# Generated by FakeRAM 2.0
VERSION 5.7 ;
BUSBITCHARS "[]" ;
PROPERTYDEFINITIONS
  MACRO width INTEGER ;
  MACRO depth INTEGER ;
  MACRO banks INTEGER ;
END PROPERTYDEFINITIONS
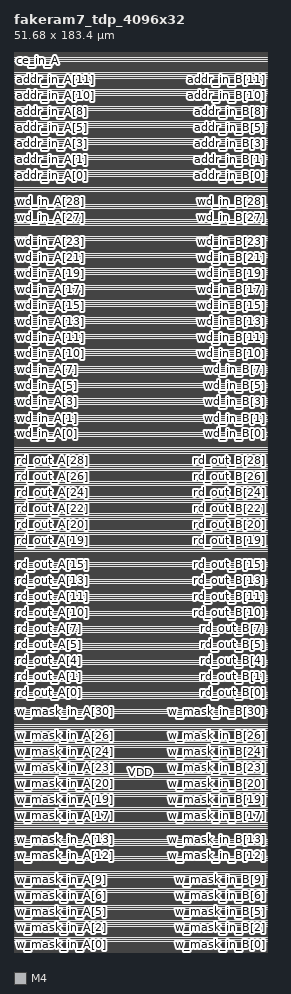
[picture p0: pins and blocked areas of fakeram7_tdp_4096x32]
MACRO fakeram7_tdp_4096x32
  PROPERTY width 32 ;
  PROPERTY depth 4096 ;
  PROPERTY banks 8 ;
  FOREIGN fakeram7_tdp_4096x32 0 0 ;
  SYMMETRY X Y ;
  SIZE 51.680 BY 183.400 ;
  CLASS BLOCK ;
  PIN w_mask_in_A[0]
    DIRECTION INPUT ;
    USE SIGNAL ;
    SHAPE ABUTMENT ;
    PORT
      LAYER M4 ;
      RECT 0.000 0.048 0.024 0.072 ;
    END
  END w_mask_in_A[0]
  PIN w_mask_in_B[0]
    DIRECTION INPUT ;
    USE SIGNAL ;
    SHAPE ABUTMENT ;
    PORT
      LAYER M4 ;
      RECT 51.656 0.048 51.680 0.072 ;
    END
  END w_mask_in_B[0]
  PIN w_mask_in_A[1]
    DIRECTION INPUT ;
    USE SIGNAL ;
    SHAPE ABUTMENT ;
    PORT
      LAYER M4 ;
      RECT 0.000 1.680 0.024 1.704 ;
    END
  END w_mask_in_A[1]
  PIN w_mask_in_B[1]
    DIRECTION INPUT ;
    USE SIGNAL ;
    SHAPE ABUTMENT ;
    PORT
      LAYER M4 ;
      RECT 51.656 1.680 51.680 1.704 ;
    END
  END w_mask_in_B[1]
  PIN w_mask_in_A[2]
    DIRECTION INPUT ;
    USE SIGNAL ;
    SHAPE ABUTMENT ;
    PORT
      LAYER M4 ;
      RECT 0.000 3.312 0.024 3.336 ;
    END
  END w_mask_in_A[2]
  PIN w_mask_in_B[2]
    DIRECTION INPUT ;
    USE SIGNAL ;
    SHAPE ABUTMENT ;
    PORT
      LAYER M4 ;
      RECT 51.656 3.312 51.680 3.336 ;
    END
  END w_mask_in_B[2]
  PIN w_mask_in_A[3]
    DIRECTION INPUT ;
    USE SIGNAL ;
    SHAPE ABUTMENT ;
    PORT
      LAYER M4 ;
      RECT 0.000 4.944 0.024 4.968 ;
    END
  END w_mask_in_A[3]
  PIN w_mask_in_B[3]
    DIRECTION INPUT ;
    USE SIGNAL ;
    SHAPE ABUTMENT ;
    PORT
      LAYER M4 ;
      RECT 51.656 4.944 51.680 4.968 ;
    END
  END w_mask_in_B[3]
  PIN w_mask_in_A[4]
    DIRECTION INPUT ;
    USE SIGNAL ;
    SHAPE ABUTMENT ;
    PORT
      LAYER M4 ;
      RECT 0.000 6.576 0.024 6.600 ;
    END
  END w_mask_in_A[4]
  PIN w_mask_in_B[4]
    DIRECTION INPUT ;
    USE SIGNAL ;
    SHAPE ABUTMENT ;
    PORT
      LAYER M4 ;
      RECT 51.656 6.576 51.680 6.600 ;
    END
  END w_mask_in_B[4]
  PIN w_mask_in_A[5]
    DIRECTION INPUT ;
    USE SIGNAL ;
    SHAPE ABUTMENT ;
    PORT
      LAYER M4 ;
      RECT 0.000 8.208 0.024 8.232 ;
    END
  END w_mask_in_A[5]
  PIN w_mask_in_B[5]
    DIRECTION INPUT ;
    USE SIGNAL ;
    SHAPE ABUTMENT ;
    PORT
      LAYER M4 ;
      RECT 51.656 8.208 51.680 8.232 ;
    END
  END w_mask_in_B[5]
  PIN w_mask_in_A[6]
    DIRECTION INPUT ;
    USE SIGNAL ;
    SHAPE ABUTMENT ;
    PORT
      LAYER M4 ;
      RECT 0.000 9.840 0.024 9.864 ;
    END
  END w_mask_in_A[6]
  PIN w_mask_in_B[6]
    DIRECTION INPUT ;
    USE SIGNAL ;
    SHAPE ABUTMENT ;
    PORT
      LAYER M4 ;
      RECT 51.656 9.840 51.680 9.864 ;
    END
  END w_mask_in_B[6]
  PIN w_mask_in_A[7]
    DIRECTION INPUT ;
    USE SIGNAL ;
    SHAPE ABUTMENT ;
    PORT
      LAYER M4 ;
      RECT 0.000 11.472 0.024 11.496 ;
    END
  END w_mask_in_A[7]
  PIN w_mask_in_B[7]
    DIRECTION INPUT ;
    USE SIGNAL ;
    SHAPE ABUTMENT ;
    PORT
      LAYER M4 ;
      RECT 51.656 11.472 51.680 11.496 ;
    END
  END w_mask_in_B[7]
  PIN w_mask_in_A[8]
    DIRECTION INPUT ;
    USE SIGNAL ;
    SHAPE ABUTMENT ;
    PORT
      LAYER M4 ;
      RECT 0.000 13.104 0.024 13.128 ;
    END
  END w_mask_in_A[8]
  PIN w_mask_in_B[8]
    DIRECTION INPUT ;
    USE SIGNAL ;
    SHAPE ABUTMENT ;
    PORT
      LAYER M4 ;
      RECT 51.656 13.104 51.680 13.128 ;
    END
  END w_mask_in_B[8]
  PIN w_mask_in_A[9]
    DIRECTION INPUT ;
    USE SIGNAL ;
    SHAPE ABUTMENT ;
    PORT
      LAYER M4 ;
      RECT 0.000 14.736 0.024 14.760 ;
    END
  END w_mask_in_A[9]
  PIN w_mask_in_B[9]
    DIRECTION INPUT ;
    USE SIGNAL ;
    SHAPE ABUTMENT ;
    PORT
      LAYER M4 ;
      RECT 51.656 14.736 51.680 14.760 ;
    END
  END w_mask_in_B[9]
  PIN w_mask_in_A[10]
    DIRECTION INPUT ;
    USE SIGNAL ;
    SHAPE ABUTMENT ;
    PORT
      LAYER M4 ;
      RECT 0.000 16.368 0.024 16.392 ;
    END
  END w_mask_in_A[10]
  PIN w_mask_in_B[10]
    DIRECTION INPUT ;
    USE SIGNAL ;
    SHAPE ABUTMENT ;
    PORT
      LAYER M4 ;
      RECT 51.656 16.368 51.680 16.392 ;
    END
  END w_mask_in_B[10]
  PIN w_mask_in_A[11]
    DIRECTION INPUT ;
    USE SIGNAL ;
    SHAPE ABUTMENT ;
    PORT
      LAYER M4 ;
      RECT 0.000 18.000 0.024 18.024 ;
    END
  END w_mask_in_A[11]
  PIN w_mask_in_B[11]
    DIRECTION INPUT ;
    USE SIGNAL ;
    SHAPE ABUTMENT ;
    PORT
      LAYER M4 ;
      RECT 51.656 18.000 51.680 18.024 ;
    END
  END w_mask_in_B[11]
  PIN w_mask_in_A[12]
    DIRECTION INPUT ;
    USE SIGNAL ;
    SHAPE ABUTMENT ;
    PORT
      LAYER M4 ;
      RECT 0.000 19.632 0.024 19.656 ;
    END
  END w_mask_in_A[12]
  PIN w_mask_in_B[12]
    DIRECTION INPUT ;
    USE SIGNAL ;
    SHAPE ABUTMENT ;
    PORT
      LAYER M4 ;
      RECT 51.656 19.632 51.680 19.656 ;
    END
  END w_mask_in_B[12]
  PIN w_mask_in_A[13]
    DIRECTION INPUT ;
    USE SIGNAL ;
    SHAPE ABUTMENT ;
    PORT
      LAYER M4 ;
      RECT 0.000 21.264 0.024 21.288 ;
    END
  END w_mask_in_A[13]
  PIN w_mask_in_B[13]
    DIRECTION INPUT ;
    USE SIGNAL ;
    SHAPE ABUTMENT ;
    PORT
      LAYER M4 ;
      RECT 51.656 21.264 51.680 21.288 ;
    END
  END w_mask_in_B[13]
  PIN w_mask_in_A[14]
    DIRECTION INPUT ;
    USE SIGNAL ;
    SHAPE ABUTMENT ;
    PORT
      LAYER M4 ;
      RECT 0.000 22.896 0.024 22.920 ;
    END
  END w_mask_in_A[14]
  PIN w_mask_in_B[14]
    DIRECTION INPUT ;
    USE SIGNAL ;
    SHAPE ABUTMENT ;
    PORT
      LAYER M4 ;
      RECT 51.656 22.896 51.680 22.920 ;
    END
  END w_mask_in_B[14]
  PIN w_mask_in_A[15]
    DIRECTION INPUT ;
    USE SIGNAL ;
    SHAPE ABUTMENT ;
    PORT
      LAYER M4 ;
      RECT 0.000 24.528 0.024 24.552 ;
    END
  END w_mask_in_A[15]
  PIN w_mask_in_B[15]
    DIRECTION INPUT ;
    USE SIGNAL ;
    SHAPE ABUTMENT ;
    PORT
      LAYER M4 ;
      RECT 51.656 24.528 51.680 24.552 ;
    END
  END w_mask_in_B[15]
  PIN w_mask_in_A[16]
    DIRECTION INPUT ;
    USE SIGNAL ;
    SHAPE ABUTMENT ;
    PORT
      LAYER M4 ;
      RECT 0.000 26.160 0.024 26.184 ;
    END
  END w_mask_in_A[16]
  PIN w_mask_in_B[16]
    DIRECTION INPUT ;
    USE SIGNAL ;
    SHAPE ABUTMENT ;
    PORT
      LAYER M4 ;
      RECT 51.656 26.160 51.680 26.184 ;
    END
  END w_mask_in_B[16]
  PIN w_mask_in_A[17]
    DIRECTION INPUT ;
    USE SIGNAL ;
    SHAPE ABUTMENT ;
    PORT
      LAYER M4 ;
      RECT 0.000 27.792 0.024 27.816 ;
    END
  END w_mask_in_A[17]
  PIN w_mask_in_B[17]
    DIRECTION INPUT ;
    USE SIGNAL ;
    SHAPE ABUTMENT ;
    PORT
      LAYER M4 ;
      RECT 51.656 27.792 51.680 27.816 ;
    END
  END w_mask_in_B[17]
  PIN w_mask_in_A[18]
    DIRECTION INPUT ;
    USE SIGNAL ;
    SHAPE ABUTMENT ;
    PORT
      LAYER M4 ;
      RECT 0.000 29.424 0.024 29.448 ;
    END
  END w_mask_in_A[18]
  PIN w_mask_in_B[18]
    DIRECTION INPUT ;
    USE SIGNAL ;
    SHAPE ABUTMENT ;
    PORT
      LAYER M4 ;
      RECT 51.656 29.424 51.680 29.448 ;
    END
  END w_mask_in_B[18]
  PIN w_mask_in_A[19]
    DIRECTION INPUT ;
    USE SIGNAL ;
    SHAPE ABUTMENT ;
    PORT
      LAYER M4 ;
      RECT 0.000 31.056 0.024 31.080 ;
    END
  END w_mask_in_A[19]
  PIN w_mask_in_B[19]
    DIRECTION INPUT ;
    USE SIGNAL ;
    SHAPE ABUTMENT ;
    PORT
      LAYER M4 ;
      RECT 51.656 31.056 51.680 31.080 ;
    END
  END w_mask_in_B[19]
  PIN w_mask_in_A[20]
    DIRECTION INPUT ;
    USE SIGNAL ;
    SHAPE ABUTMENT ;
    PORT
      LAYER M4 ;
      RECT 0.000 32.688 0.024 32.712 ;
    END
  END w_mask_in_A[20]
  PIN w_mask_in_B[20]
    DIRECTION INPUT ;
    USE SIGNAL ;
    SHAPE ABUTMENT ;
    PORT
      LAYER M4 ;
      RECT 51.656 32.688 51.680 32.712 ;
    END
  END w_mask_in_B[20]
  PIN w_mask_in_A[21]
    DIRECTION INPUT ;
    USE SIGNAL ;
    SHAPE ABUTMENT ;
    PORT
      LAYER M4 ;
      RECT 0.000 34.320 0.024 34.344 ;
    END
  END w_mask_in_A[21]
  PIN w_mask_in_B[21]
    DIRECTION INPUT ;
    USE SIGNAL ;
    SHAPE ABUTMENT ;
    PORT
      LAYER M4 ;
      RECT 51.656 34.320 51.680 34.344 ;
    END
  END w_mask_in_B[21]
  PIN w_mask_in_A[22]
    DIRECTION INPUT ;
    USE SIGNAL ;
    SHAPE ABUTMENT ;
    PORT
      LAYER M4 ;
      RECT 0.000 35.952 0.024 35.976 ;
    END
  END w_mask_in_A[22]
  PIN w_mask_in_B[22]
    DIRECTION INPUT ;
    USE SIGNAL ;
    SHAPE ABUTMENT ;
    PORT
      LAYER M4 ;
      RECT 51.656 35.952 51.680 35.976 ;
    END
  END w_mask_in_B[22]
  PIN w_mask_in_A[23]
    DIRECTION INPUT ;
    USE SIGNAL ;
    SHAPE ABUTMENT ;
    PORT
      LAYER M4 ;
      RECT 0.000 37.584 0.024 37.608 ;
    END
  END w_mask_in_A[23]
  PIN w_mask_in_B[23]
    DIRECTION INPUT ;
    USE SIGNAL ;
    SHAPE ABUTMENT ;
    PORT
      LAYER M4 ;
      RECT 51.656 37.584 51.680 37.608 ;
    END
  END w_mask_in_B[23]
  PIN w_mask_in_A[24]
    DIRECTION INPUT ;
    USE SIGNAL ;
    SHAPE ABUTMENT ;
    PORT
      LAYER M4 ;
      RECT 0.000 39.216 0.024 39.240 ;
    END
  END w_mask_in_A[24]
  PIN w_mask_in_B[24]
    DIRECTION INPUT ;
    USE SIGNAL ;
    SHAPE ABUTMENT ;
    PORT
      LAYER M4 ;
      RECT 51.656 39.216 51.680 39.240 ;
    END
  END w_mask_in_B[24]
  PIN w_mask_in_A[25]
    DIRECTION INPUT ;
    USE SIGNAL ;
    SHAPE ABUTMENT ;
    PORT
      LAYER M4 ;
      RECT 0.000 40.848 0.024 40.872 ;
    END
  END w_mask_in_A[25]
  PIN w_mask_in_B[25]
    DIRECTION INPUT ;
    USE SIGNAL ;
    SHAPE ABUTMENT ;
    PORT
      LAYER M4 ;
      RECT 51.656 40.848 51.680 40.872 ;
    END
  END w_mask_in_B[25]
  PIN w_mask_in_A[26]
    DIRECTION INPUT ;
    USE SIGNAL ;
    SHAPE ABUTMENT ;
    PORT
      LAYER M4 ;
      RECT 0.000 42.480 0.024 42.504 ;
    END
  END w_mask_in_A[26]
  PIN w_mask_in_B[26]
    DIRECTION INPUT ;
    USE SIGNAL ;
    SHAPE ABUTMENT ;
    PORT
      LAYER M4 ;
      RECT 51.656 42.480 51.680 42.504 ;
    END
  END w_mask_in_B[26]
  PIN w_mask_in_A[27]
    DIRECTION INPUT ;
    USE SIGNAL ;
    SHAPE ABUTMENT ;
    PORT
      LAYER M4 ;
      RECT 0.000 44.112 0.024 44.136 ;
    END
  END w_mask_in_A[27]
  PIN w_mask_in_B[27]
    DIRECTION INPUT ;
    USE SIGNAL ;
    SHAPE ABUTMENT ;
    PORT
      LAYER M4 ;
      RECT 51.656 44.112 51.680 44.136 ;
    END
  END w_mask_in_B[27]
  PIN w_mask_in_A[28]
    DIRECTION INPUT ;
    USE SIGNAL ;
    SHAPE ABUTMENT ;
    PORT
      LAYER M4 ;
      RECT 0.000 45.744 0.024 45.768 ;
    END
  END w_mask_in_A[28]
  PIN w_mask_in_B[28]
    DIRECTION INPUT ;
    USE SIGNAL ;
    SHAPE ABUTMENT ;
    PORT
      LAYER M4 ;
      RECT 51.656 45.744 51.680 45.768 ;
    END
  END w_mask_in_B[28]
  PIN w_mask_in_A[29]
    DIRECTION INPUT ;
    USE SIGNAL ;
    SHAPE ABUTMENT ;
    PORT
      LAYER M4 ;
      RECT 0.000 47.376 0.024 47.400 ;
    END
  END w_mask_in_A[29]
  PIN w_mask_in_B[29]
    DIRECTION INPUT ;
    USE SIGNAL ;
    SHAPE ABUTMENT ;
    PORT
      LAYER M4 ;
      RECT 51.656 47.376 51.680 47.400 ;
    END
  END w_mask_in_B[29]
  PIN w_mask_in_A[30]
    DIRECTION INPUT ;
    USE SIGNAL ;
    SHAPE ABUTMENT ;
    PORT
      LAYER M4 ;
      RECT 0.000 49.008 0.024 49.032 ;
    END
  END w_mask_in_A[30]
  PIN w_mask_in_B[30]
    DIRECTION INPUT ;
    USE SIGNAL ;
    SHAPE ABUTMENT ;
    PORT
      LAYER M4 ;
      RECT 51.656 49.008 51.680 49.032 ;
    END
  END w_mask_in_B[30]
  PIN w_mask_in_A[31]
    DIRECTION INPUT ;
    USE SIGNAL ;
    SHAPE ABUTMENT ;
    PORT
      LAYER M4 ;
      RECT 0.000 50.640 0.024 50.664 ;
    END
  END w_mask_in_A[31]
  PIN w_mask_in_B[31]
    DIRECTION INPUT ;
    USE SIGNAL ;
    SHAPE ABUTMENT ;
    PORT
      LAYER M4 ;
      RECT 51.656 50.640 51.680 50.664 ;
    END
  END w_mask_in_B[31]
  PIN rd_out_A[0]
    DIRECTION OUTPUT ;
    USE SIGNAL ;
    SHAPE ABUTMENT ;
    PORT
      LAYER M4 ;
      RECT 0.000 52.800 0.024 52.824 ;
    END
  END rd_out_A[0]
  PIN rd_out_B[0]
    DIRECTION OUTPUT ;
    USE SIGNAL ;
    SHAPE ABUTMENT ;
    PORT
      LAYER M4 ;
      RECT 51.656 52.800 51.680 52.824 ;
    END
  END rd_out_B[0]
  PIN rd_out_A[1]
    DIRECTION OUTPUT ;
    USE SIGNAL ;
    SHAPE ABUTMENT ;
    PORT
      LAYER M4 ;
      RECT 0.000 54.432 0.024 54.456 ;
    END
  END rd_out_A[1]
  PIN rd_out_B[1]
    DIRECTION OUTPUT ;
    USE SIGNAL ;
    SHAPE ABUTMENT ;
    PORT
      LAYER M4 ;
      RECT 51.656 54.432 51.680 54.456 ;
    END
  END rd_out_B[1]
  PIN rd_out_A[2]
    DIRECTION OUTPUT ;
    USE SIGNAL ;
    SHAPE ABUTMENT ;
    PORT
      LAYER M4 ;
      RECT 0.000 56.064 0.024 56.088 ;
    END
  END rd_out_A[2]
  PIN rd_out_B[2]
    DIRECTION OUTPUT ;
    USE SIGNAL ;
    SHAPE ABUTMENT ;
    PORT
      LAYER M4 ;
      RECT 51.656 56.064 51.680 56.088 ;
    END
  END rd_out_B[2]
  PIN rd_out_A[3]
    DIRECTION OUTPUT ;
    USE SIGNAL ;
    SHAPE ABUTMENT ;
    PORT
      LAYER M4 ;
      RECT 0.000 57.696 0.024 57.720 ;
    END
  END rd_out_A[3]
  PIN rd_out_B[3]
    DIRECTION OUTPUT ;
    USE SIGNAL ;
    SHAPE ABUTMENT ;
    PORT
      LAYER M4 ;
      RECT 51.656 57.696 51.680 57.720 ;
    END
  END rd_out_B[3]
  PIN rd_out_A[4]
    DIRECTION OUTPUT ;
    USE SIGNAL ;
    SHAPE ABUTMENT ;
    PORT
      LAYER M4 ;
      RECT 0.000 59.328 0.024 59.352 ;
    END
  END rd_out_A[4]
  PIN rd_out_B[4]
    DIRECTION OUTPUT ;
    USE SIGNAL ;
    SHAPE ABUTMENT ;
    PORT
      LAYER M4 ;
      RECT 51.656 59.328 51.680 59.352 ;
    END
  END rd_out_B[4]
  PIN rd_out_A[5]
    DIRECTION OUTPUT ;
    USE SIGNAL ;
    SHAPE ABUTMENT ;
    PORT
      LAYER M4 ;
      RECT 0.000 60.960 0.024 60.984 ;
    END
  END rd_out_A[5]
  PIN rd_out_B[5]
    DIRECTION OUTPUT ;
    USE SIGNAL ;
    SHAPE ABUTMENT ;
    PORT
      LAYER M4 ;
      RECT 51.656 60.960 51.680 60.984 ;
    END
  END rd_out_B[5]
  PIN rd_out_A[6]
    DIRECTION OUTPUT ;
    USE SIGNAL ;
    SHAPE ABUTMENT ;
    PORT
      LAYER M4 ;
      RECT 0.000 62.592 0.024 62.616 ;
    END
  END rd_out_A[6]
  PIN rd_out_B[6]
    DIRECTION OUTPUT ;
    USE SIGNAL ;
    SHAPE ABUTMENT ;
    PORT
      LAYER M4 ;
      RECT 51.656 62.592 51.680 62.616 ;
    END
  END rd_out_B[6]
  PIN rd_out_A[7]
    DIRECTION OUTPUT ;
    USE SIGNAL ;
    SHAPE ABUTMENT ;
    PORT
      LAYER M4 ;
      RECT 0.000 64.224 0.024 64.248 ;
    END
  END rd_out_A[7]
  PIN rd_out_B[7]
    DIRECTION OUTPUT ;
    USE SIGNAL ;
    SHAPE ABUTMENT ;
    PORT
      LAYER M4 ;
      RECT 51.656 64.224 51.680 64.248 ;
    END
  END rd_out_B[7]
  PIN rd_out_A[8]
    DIRECTION OUTPUT ;
    USE SIGNAL ;
    SHAPE ABUTMENT ;
    PORT
      LAYER M4 ;
      RECT 0.000 65.856 0.024 65.880 ;
    END
  END rd_out_A[8]
  PIN rd_out_B[8]
    DIRECTION OUTPUT ;
    USE SIGNAL ;
    SHAPE ABUTMENT ;
    PORT
      LAYER M4 ;
      RECT 51.656 65.856 51.680 65.880 ;
    END
  END rd_out_B[8]
  PIN rd_out_A[9]
    DIRECTION OUTPUT ;
    USE SIGNAL ;
    SHAPE ABUTMENT ;
    PORT
      LAYER M4 ;
      RECT 0.000 67.488 0.024 67.512 ;
    END
  END rd_out_A[9]
  PIN rd_out_B[9]
    DIRECTION OUTPUT ;
    USE SIGNAL ;
    SHAPE ABUTMENT ;
    PORT
      LAYER M4 ;
      RECT 51.656 67.488 51.680 67.512 ;
    END
  END rd_out_B[9]
  PIN rd_out_A[10]
    DIRECTION OUTPUT ;
    USE SIGNAL ;
    SHAPE ABUTMENT ;
    PORT
      LAYER M4 ;
      RECT 0.000 69.120 0.024 69.144 ;
    END
  END rd_out_A[10]
  PIN rd_out_B[10]
    DIRECTION OUTPUT ;
    USE SIGNAL ;
    SHAPE ABUTMENT ;
    PORT
      LAYER M4 ;
      RECT 51.656 69.120 51.680 69.144 ;
    END
  END rd_out_B[10]
  PIN rd_out_A[11]
    DIRECTION OUTPUT ;
    USE SIGNAL ;
    SHAPE ABUTMENT ;
    PORT
      LAYER M4 ;
      RECT 0.000 70.752 0.024 70.776 ;
    END
  END rd_out_A[11]
  PIN rd_out_B[11]
    DIRECTION OUTPUT ;
    USE SIGNAL ;
    SHAPE ABUTMENT ;
    PORT
      LAYER M4 ;
      RECT 51.656 70.752 51.680 70.776 ;
    END
  END rd_out_B[11]
  PIN rd_out_A[12]
    DIRECTION OUTPUT ;
    USE SIGNAL ;
    SHAPE ABUTMENT ;
    PORT
      LAYER M4 ;
      RECT 0.000 72.384 0.024 72.408 ;
    END
  END rd_out_A[12]
  PIN rd_out_B[12]
    DIRECTION OUTPUT ;
    USE SIGNAL ;
    SHAPE ABUTMENT ;
    PORT
      LAYER M4 ;
      RECT 51.656 72.384 51.680 72.408 ;
    END
  END rd_out_B[12]
  PIN rd_out_A[13]
    DIRECTION OUTPUT ;
    USE SIGNAL ;
    SHAPE ABUTMENT ;
    PORT
      LAYER M4 ;
      RECT 0.000 74.016 0.024 74.040 ;
    END
  END rd_out_A[13]
  PIN rd_out_B[13]
    DIRECTION OUTPUT ;
    USE SIGNAL ;
    SHAPE ABUTMENT ;
    PORT
      LAYER M4 ;
      RECT 51.656 74.016 51.680 74.040 ;
    END
  END rd_out_B[13]
  PIN rd_out_A[14]
    DIRECTION OUTPUT ;
    USE SIGNAL ;
    SHAPE ABUTMENT ;
    PORT
      LAYER M4 ;
      RECT 0.000 75.648 0.024 75.672 ;
    END
  END rd_out_A[14]
  PIN rd_out_B[14]
    DIRECTION OUTPUT ;
    USE SIGNAL ;
    SHAPE ABUTMENT ;
    PORT
      LAYER M4 ;
      RECT 51.656 75.648 51.680 75.672 ;
    END
  END rd_out_B[14]
  PIN rd_out_A[15]
    DIRECTION OUTPUT ;
    USE SIGNAL ;
    SHAPE ABUTMENT ;
    PORT
      LAYER M4 ;
      RECT 0.000 77.280 0.024 77.304 ;
    END
  END rd_out_A[15]
  PIN rd_out_B[15]
    DIRECTION OUTPUT ;
    USE SIGNAL ;
    SHAPE ABUTMENT ;
    PORT
      LAYER M4 ;
      RECT 51.656 77.280 51.680 77.304 ;
    END
  END rd_out_B[15]
  PIN rd_out_A[16]
    DIRECTION OUTPUT ;
    USE SIGNAL ;
    SHAPE ABUTMENT ;
    PORT
      LAYER M4 ;
      RECT 0.000 78.912 0.024 78.936 ;
    END
  END rd_out_A[16]
  PIN rd_out_B[16]
    DIRECTION OUTPUT ;
    USE SIGNAL ;
    SHAPE ABUTMENT ;
    PORT
      LAYER M4 ;
      RECT 51.656 78.912 51.680 78.936 ;
    END
  END rd_out_B[16]
  PIN rd_out_A[17]
    DIRECTION OUTPUT ;
    USE SIGNAL ;
    SHAPE ABUTMENT ;
    PORT
      LAYER M4 ;
      RECT 0.000 80.544 0.024 80.568 ;
    END
  END rd_out_A[17]
  PIN rd_out_B[17]
    DIRECTION OUTPUT ;
    USE SIGNAL ;
    SHAPE ABUTMENT ;
    PORT
      LAYER M4 ;
      RECT 51.656 80.544 51.680 80.568 ;
    END
  END rd_out_B[17]
  PIN rd_out_A[18]
    DIRECTION OUTPUT ;
    USE SIGNAL ;
    SHAPE ABUTMENT ;
    PORT
      LAYER M4 ;
      RECT 0.000 82.176 0.024 82.200 ;
    END
  END rd_out_A[18]
  PIN rd_out_B[18]
    DIRECTION OUTPUT ;
    USE SIGNAL ;
    SHAPE ABUTMENT ;
    PORT
      LAYER M4 ;
      RECT 51.656 82.176 51.680 82.200 ;
    END
  END rd_out_B[18]
  PIN rd_out_A[19]
    DIRECTION OUTPUT ;
    USE SIGNAL ;
    SHAPE ABUTMENT ;
    PORT
      LAYER M4 ;
      RECT 0.000 83.808 0.024 83.832 ;
    END
  END rd_out_A[19]
  PIN rd_out_B[19]
    DIRECTION OUTPUT ;
    USE SIGNAL ;
    SHAPE ABUTMENT ;
    PORT
      LAYER M4 ;
      RECT 51.656 83.808 51.680 83.832 ;
    END
  END rd_out_B[19]
  PIN rd_out_A[20]
    DIRECTION OUTPUT ;
    USE SIGNAL ;
    SHAPE ABUTMENT ;
    PORT
      LAYER M4 ;
      RECT 0.000 85.440 0.024 85.464 ;
    END
  END rd_out_A[20]
  PIN rd_out_B[20]
    DIRECTION OUTPUT ;
    USE SIGNAL ;
    SHAPE ABUTMENT ;
    PORT
      LAYER M4 ;
      RECT 51.656 85.440 51.680 85.464 ;
    END
  END rd_out_B[20]
  PIN rd_out_A[21]
    DIRECTION OUTPUT ;
    USE SIGNAL ;
    SHAPE ABUTMENT ;
    PORT
      LAYER M4 ;
      RECT 0.000 87.072 0.024 87.096 ;
    END
  END rd_out_A[21]
  PIN rd_out_B[21]
    DIRECTION OUTPUT ;
    USE SIGNAL ;
    SHAPE ABUTMENT ;
    PORT
      LAYER M4 ;
      RECT 51.656 87.072 51.680 87.096 ;
    END
  END rd_out_B[21]
  PIN rd_out_A[22]
    DIRECTION OUTPUT ;
    USE SIGNAL ;
    SHAPE ABUTMENT ;
    PORT
      LAYER M4 ;
      RECT 0.000 88.704 0.024 88.728 ;
    END
  END rd_out_A[22]
  PIN rd_out_B[22]
    DIRECTION OUTPUT ;
    USE SIGNAL ;
    SHAPE ABUTMENT ;
    PORT
      LAYER M4 ;
      RECT 51.656 88.704 51.680 88.728 ;
    END
  END rd_out_B[22]
  PIN rd_out_A[23]
    DIRECTION OUTPUT ;
    USE SIGNAL ;
    SHAPE ABUTMENT ;
    PORT
      LAYER M4 ;
      RECT 0.000 90.336 0.024 90.360 ;
    END
  END rd_out_A[23]
  PIN rd_out_B[23]
    DIRECTION OUTPUT ;
    USE SIGNAL ;
    SHAPE ABUTMENT ;
    PORT
      LAYER M4 ;
      RECT 51.656 90.336 51.680 90.360 ;
    END
  END rd_out_B[23]
  PIN rd_out_A[24]
    DIRECTION OUTPUT ;
    USE SIGNAL ;
    SHAPE ABUTMENT ;
    PORT
      LAYER M4 ;
      RECT 0.000 91.968 0.024 91.992 ;
    END
  END rd_out_A[24]
  PIN rd_out_B[24]
    DIRECTION OUTPUT ;
    USE SIGNAL ;
    SHAPE ABUTMENT ;
    PORT
      LAYER M4 ;
      RECT 51.656 91.968 51.680 91.992 ;
    END
  END rd_out_B[24]
  PIN rd_out_A[25]
    DIRECTION OUTPUT ;
    USE SIGNAL ;
    SHAPE ABUTMENT ;
    PORT
      LAYER M4 ;
      RECT 0.000 93.600 0.024 93.624 ;
    END
  END rd_out_A[25]
  PIN rd_out_B[25]
    DIRECTION OUTPUT ;
    USE SIGNAL ;
    SHAPE ABUTMENT ;
    PORT
      LAYER M4 ;
      RECT 51.656 93.600 51.680 93.624 ;
    END
  END rd_out_B[25]
  PIN rd_out_A[26]
    DIRECTION OUTPUT ;
    USE SIGNAL ;
    SHAPE ABUTMENT ;
    PORT
      LAYER M4 ;
      RECT 0.000 95.232 0.024 95.256 ;
    END
  END rd_out_A[26]
  PIN rd_out_B[26]
    DIRECTION OUTPUT ;
    USE SIGNAL ;
    SHAPE ABUTMENT ;
    PORT
      LAYER M4 ;
      RECT 51.656 95.232 51.680 95.256 ;
    END
  END rd_out_B[26]
  PIN rd_out_A[27]
    DIRECTION OUTPUT ;
    USE SIGNAL ;
    SHAPE ABUTMENT ;
    PORT
      LAYER M4 ;
      RECT 0.000 96.864 0.024 96.888 ;
    END
  END rd_out_A[27]
  PIN rd_out_B[27]
    DIRECTION OUTPUT ;
    USE SIGNAL ;
    SHAPE ABUTMENT ;
    PORT
      LAYER M4 ;
      RECT 51.656 96.864 51.680 96.888 ;
    END
  END rd_out_B[27]
  PIN rd_out_A[28]
    DIRECTION OUTPUT ;
    USE SIGNAL ;
    SHAPE ABUTMENT ;
    PORT
      LAYER M4 ;
      RECT 0.000 98.496 0.024 98.520 ;
    END
  END rd_out_A[28]
  PIN rd_out_B[28]
    DIRECTION OUTPUT ;
    USE SIGNAL ;
    SHAPE ABUTMENT ;
    PORT
      LAYER M4 ;
      RECT 51.656 98.496 51.680 98.520 ;
    END
  END rd_out_B[28]
  PIN rd_out_A[29]
    DIRECTION OUTPUT ;
    USE SIGNAL ;
    SHAPE ABUTMENT ;
    PORT
      LAYER M4 ;
      RECT 0.000 100.128 0.024 100.152 ;
    END
  END rd_out_A[29]
  PIN rd_out_B[29]
    DIRECTION OUTPUT ;
    USE SIGNAL ;
    SHAPE ABUTMENT ;
    PORT
      LAYER M4 ;
      RECT 51.656 100.128 51.680 100.152 ;
    END
  END rd_out_B[29]
  PIN rd_out_A[30]
    DIRECTION OUTPUT ;
    USE SIGNAL ;
    SHAPE ABUTMENT ;
    PORT
      LAYER M4 ;
      RECT 0.000 101.760 0.024 101.784 ;
    END
  END rd_out_A[30]
  PIN rd_out_B[30]
    DIRECTION OUTPUT ;
    USE SIGNAL ;
    SHAPE ABUTMENT ;
    PORT
      LAYER M4 ;
      RECT 51.656 101.760 51.680 101.784 ;
    END
  END rd_out_B[30]
  PIN rd_out_A[31]
    DIRECTION OUTPUT ;
    USE SIGNAL ;
    SHAPE ABUTMENT ;
    PORT
      LAYER M4 ;
      RECT 0.000 103.392 0.024 103.416 ;
    END
  END rd_out_A[31]
  PIN rd_out_B[31]
    DIRECTION OUTPUT ;
    USE SIGNAL ;
    SHAPE ABUTMENT ;
    PORT
      LAYER M4 ;
      RECT 51.656 103.392 51.680 103.416 ;
    END
  END rd_out_B[31]
  PIN wd_in_A[0]
    DIRECTION INPUT ;
    USE SIGNAL ;
    SHAPE ABUTMENT ;
    PORT
      LAYER M4 ;
      RECT 0.000 105.552 0.024 105.576 ;
    END
  END wd_in_A[0]
  PIN wd_in_B[0]
    DIRECTION INPUT ;
    USE SIGNAL ;
    SHAPE ABUTMENT ;
    PORT
      LAYER M4 ;
      RECT 51.656 105.552 51.680 105.576 ;
    END
  END wd_in_B[0]
  PIN wd_in_A[1]
    DIRECTION INPUT ;
    USE SIGNAL ;
    SHAPE ABUTMENT ;
    PORT
      LAYER M4 ;
      RECT 0.000 107.184 0.024 107.208 ;
    END
  END wd_in_A[1]
  PIN wd_in_B[1]
    DIRECTION INPUT ;
    USE SIGNAL ;
    SHAPE ABUTMENT ;
    PORT
      LAYER M4 ;
      RECT 51.656 107.184 51.680 107.208 ;
    END
  END wd_in_B[1]
  PIN wd_in_A[2]
    DIRECTION INPUT ;
    USE SIGNAL ;
    SHAPE ABUTMENT ;
    PORT
      LAYER M4 ;
      RECT 0.000 108.816 0.024 108.840 ;
    END
  END wd_in_A[2]
  PIN wd_in_B[2]
    DIRECTION INPUT ;
    USE SIGNAL ;
    SHAPE ABUTMENT ;
    PORT
      LAYER M4 ;
      RECT 51.656 108.816 51.680 108.840 ;
    END
  END wd_in_B[2]
  PIN wd_in_A[3]
    DIRECTION INPUT ;
    USE SIGNAL ;
    SHAPE ABUTMENT ;
    PORT
      LAYER M4 ;
      RECT 0.000 110.448 0.024 110.472 ;
    END
  END wd_in_A[3]
  PIN wd_in_B[3]
    DIRECTION INPUT ;
    USE SIGNAL ;
    SHAPE ABUTMENT ;
    PORT
      LAYER M4 ;
      RECT 51.656 110.448 51.680 110.472 ;
    END
  END wd_in_B[3]
  PIN wd_in_A[4]
    DIRECTION INPUT ;
    USE SIGNAL ;
    SHAPE ABUTMENT ;
    PORT
      LAYER M4 ;
      RECT 0.000 112.080 0.024 112.104 ;
    END
  END wd_in_A[4]
  PIN wd_in_B[4]
    DIRECTION INPUT ;
    USE SIGNAL ;
    SHAPE ABUTMENT ;
    PORT
      LAYER M4 ;
      RECT 51.656 112.080 51.680 112.104 ;
    END
  END wd_in_B[4]
  PIN wd_in_A[5]
    DIRECTION INPUT ;
    USE SIGNAL ;
    SHAPE ABUTMENT ;
    PORT
      LAYER M4 ;
      RECT 0.000 113.712 0.024 113.736 ;
    END
  END wd_in_A[5]
  PIN wd_in_B[5]
    DIRECTION INPUT ;
    USE SIGNAL ;
    SHAPE ABUTMENT ;
    PORT
      LAYER M4 ;
      RECT 51.656 113.712 51.680 113.736 ;
    END
  END wd_in_B[5]
  PIN wd_in_A[6]
    DIRECTION INPUT ;
    USE SIGNAL ;
    SHAPE ABUTMENT ;
    PORT
      LAYER M4 ;
      RECT 0.000 115.344 0.024 115.368 ;
    END
  END wd_in_A[6]
  PIN wd_in_B[6]
    DIRECTION INPUT ;
    USE SIGNAL ;
    SHAPE ABUTMENT ;
    PORT
      LAYER M4 ;
      RECT 51.656 115.344 51.680 115.368 ;
    END
  END wd_in_B[6]
  PIN wd_in_A[7]
    DIRECTION INPUT ;
    USE SIGNAL ;
    SHAPE ABUTMENT ;
    PORT
      LAYER M4 ;
      RECT 0.000 116.976 0.024 117.000 ;
    END
  END wd_in_A[7]
  PIN wd_in_B[7]
    DIRECTION INPUT ;
    USE SIGNAL ;
    SHAPE ABUTMENT ;
    PORT
      LAYER M4 ;
      RECT 51.656 116.976 51.680 117.000 ;
    END
  END wd_in_B[7]
  PIN wd_in_A[8]
    DIRECTION INPUT ;
    USE SIGNAL ;
    SHAPE ABUTMENT ;
    PORT
      LAYER M4 ;
      RECT 0.000 118.608 0.024 118.632 ;
    END
  END wd_in_A[8]
  PIN wd_in_B[8]
    DIRECTION INPUT ;
    USE SIGNAL ;
    SHAPE ABUTMENT ;
    PORT
      LAYER M4 ;
      RECT 51.656 118.608 51.680 118.632 ;
    END
  END wd_in_B[8]
  PIN wd_in_A[9]
    DIRECTION INPUT ;
    USE SIGNAL ;
    SHAPE ABUTMENT ;
    PORT
      LAYER M4 ;
      RECT 0.000 120.240 0.024 120.264 ;
    END
  END wd_in_A[9]
  PIN wd_in_B[9]
    DIRECTION INPUT ;
    USE SIGNAL ;
    SHAPE ABUTMENT ;
    PORT
      LAYER M4 ;
      RECT 51.656 120.240 51.680 120.264 ;
    END
  END wd_in_B[9]
  PIN wd_in_A[10]
    DIRECTION INPUT ;
    USE SIGNAL ;
    SHAPE ABUTMENT ;
    PORT
      LAYER M4 ;
      RECT 0.000 121.872 0.024 121.896 ;
    END
  END wd_in_A[10]
  PIN wd_in_B[10]
    DIRECTION INPUT ;
    USE SIGNAL ;
    SHAPE ABUTMENT ;
    PORT
      LAYER M4 ;
      RECT 51.656 121.872 51.680 121.896 ;
    END
  END wd_in_B[10]
  PIN wd_in_A[11]
    DIRECTION INPUT ;
    USE SIGNAL ;
    SHAPE ABUTMENT ;
    PORT
      LAYER M4 ;
      RECT 0.000 123.504 0.024 123.528 ;
    END
  END wd_in_A[11]
  PIN wd_in_B[11]
    DIRECTION INPUT ;
    USE SIGNAL ;
    SHAPE ABUTMENT ;
    PORT
      LAYER M4 ;
      RECT 51.656 123.504 51.680 123.528 ;
    END
  END wd_in_B[11]
  PIN wd_in_A[12]
    DIRECTION INPUT ;
    USE SIGNAL ;
    SHAPE ABUTMENT ;
    PORT
      LAYER M4 ;
      RECT 0.000 125.136 0.024 125.160 ;
    END
  END wd_in_A[12]
  PIN wd_in_B[12]
    DIRECTION INPUT ;
    USE SIGNAL ;
    SHAPE ABUTMENT ;
    PORT
      LAYER M4 ;
      RECT 51.656 125.136 51.680 125.160 ;
    END
  END wd_in_B[12]
  PIN wd_in_A[13]
    DIRECTION INPUT ;
    USE SIGNAL ;
    SHAPE ABUTMENT ;
    PORT
      LAYER M4 ;
      RECT 0.000 126.768 0.024 126.792 ;
    END
  END wd_in_A[13]
  PIN wd_in_B[13]
    DIRECTION INPUT ;
    USE SIGNAL ;
    SHAPE ABUTMENT ;
    PORT
      LAYER M4 ;
      RECT 51.656 126.768 51.680 126.792 ;
    END
  END wd_in_B[13]
  PIN wd_in_A[14]
    DIRECTION INPUT ;
    USE SIGNAL ;
    SHAPE ABUTMENT ;
    PORT
      LAYER M4 ;
      RECT 0.000 128.400 0.024 128.424 ;
    END
  END wd_in_A[14]
  PIN wd_in_B[14]
    DIRECTION INPUT ;
    USE SIGNAL ;
    SHAPE ABUTMENT ;
    PORT
      LAYER M4 ;
      RECT 51.656 128.400 51.680 128.424 ;
    END
  END wd_in_B[14]
  PIN wd_in_A[15]
    DIRECTION INPUT ;
    USE SIGNAL ;
    SHAPE ABUTMENT ;
    PORT
      LAYER M4 ;
      RECT 0.000 130.032 0.024 130.056 ;
    END
  END wd_in_A[15]
  PIN wd_in_B[15]
    DIRECTION INPUT ;
    USE SIGNAL ;
    SHAPE ABUTMENT ;
    PORT
      LAYER M4 ;
      RECT 51.656 130.032 51.680 130.056 ;
    END
  END wd_in_B[15]
  PIN wd_in_A[16]
    DIRECTION INPUT ;
    USE SIGNAL ;
    SHAPE ABUTMENT ;
    PORT
      LAYER M4 ;
      RECT 0.000 131.664 0.024 131.688 ;
    END
  END wd_in_A[16]
  PIN wd_in_B[16]
    DIRECTION INPUT ;
    USE SIGNAL ;
    SHAPE ABUTMENT ;
    PORT
      LAYER M4 ;
      RECT 51.656 131.664 51.680 131.688 ;
    END
  END wd_in_B[16]
  PIN wd_in_A[17]
    DIRECTION INPUT ;
    USE SIGNAL ;
    SHAPE ABUTMENT ;
    PORT
      LAYER M4 ;
      RECT 0.000 133.296 0.024 133.320 ;
    END
  END wd_in_A[17]
  PIN wd_in_B[17]
    DIRECTION INPUT ;
    USE SIGNAL ;
    SHAPE ABUTMENT ;
    PORT
      LAYER M4 ;
      RECT 51.656 133.296 51.680 133.320 ;
    END
  END wd_in_B[17]
  PIN wd_in_A[18]
    DIRECTION INPUT ;
    USE SIGNAL ;
    SHAPE ABUTMENT ;
    PORT
      LAYER M4 ;
      RECT 0.000 134.928 0.024 134.952 ;
    END
  END wd_in_A[18]
  PIN wd_in_B[18]
    DIRECTION INPUT ;
    USE SIGNAL ;
    SHAPE ABUTMENT ;
    PORT
      LAYER M4 ;
      RECT 51.656 134.928 51.680 134.952 ;
    END
  END wd_in_B[18]
  PIN wd_in_A[19]
    DIRECTION INPUT ;
    USE SIGNAL ;
    SHAPE ABUTMENT ;
    PORT
      LAYER M4 ;
      RECT 0.000 136.560 0.024 136.584 ;
    END
  END wd_in_A[19]
  PIN wd_in_B[19]
    DIRECTION INPUT ;
    USE SIGNAL ;
    SHAPE ABUTMENT ;
    PORT
      LAYER M4 ;
      RECT 51.656 136.560 51.680 136.584 ;
    END
  END wd_in_B[19]
  PIN wd_in_A[20]
    DIRECTION INPUT ;
    USE SIGNAL ;
    SHAPE ABUTMENT ;
    PORT
      LAYER M4 ;
      RECT 0.000 138.192 0.024 138.216 ;
    END
  END wd_in_A[20]
  PIN wd_in_B[20]
    DIRECTION INPUT ;
    USE SIGNAL ;
    SHAPE ABUTMENT ;
    PORT
      LAYER M4 ;
      RECT 51.656 138.192 51.680 138.216 ;
    END
  END wd_in_B[20]
  PIN wd_in_A[21]
    DIRECTION INPUT ;
    USE SIGNAL ;
    SHAPE ABUTMENT ;
    PORT
      LAYER M4 ;
      RECT 0.000 139.824 0.024 139.848 ;
    END
  END wd_in_A[21]
  PIN wd_in_B[21]
    DIRECTION INPUT ;
    USE SIGNAL ;
    SHAPE ABUTMENT ;
    PORT
      LAYER M4 ;
      RECT 51.656 139.824 51.680 139.848 ;
    END
  END wd_in_B[21]
  PIN wd_in_A[22]
    DIRECTION INPUT ;
    USE SIGNAL ;
    SHAPE ABUTMENT ;
    PORT
      LAYER M4 ;
      RECT 0.000 141.456 0.024 141.480 ;
    END
  END wd_in_A[22]
  PIN wd_in_B[22]
    DIRECTION INPUT ;
    USE SIGNAL ;
    SHAPE ABUTMENT ;
    PORT
      LAYER M4 ;
      RECT 51.656 141.456 51.680 141.480 ;
    END
  END wd_in_B[22]
  PIN wd_in_A[23]
    DIRECTION INPUT ;
    USE SIGNAL ;
    SHAPE ABUTMENT ;
    PORT
      LAYER M4 ;
      RECT 0.000 143.088 0.024 143.112 ;
    END
  END wd_in_A[23]
  PIN wd_in_B[23]
    DIRECTION INPUT ;
    USE SIGNAL ;
    SHAPE ABUTMENT ;
    PORT
      LAYER M4 ;
      RECT 51.656 143.088 51.680 143.112 ;
    END
  END wd_in_B[23]
  PIN wd_in_A[24]
    DIRECTION INPUT ;
    USE SIGNAL ;
    SHAPE ABUTMENT ;
    PORT
      LAYER M4 ;
      RECT 0.000 144.720 0.024 144.744 ;
    END
  END wd_in_A[24]
  PIN wd_in_B[24]
    DIRECTION INPUT ;
    USE SIGNAL ;
    SHAPE ABUTMENT ;
    PORT
      LAYER M4 ;
      RECT 51.656 144.720 51.680 144.744 ;
    END
  END wd_in_B[24]
  PIN wd_in_A[25]
    DIRECTION INPUT ;
    USE SIGNAL ;
    SHAPE ABUTMENT ;
    PORT
      LAYER M4 ;
      RECT 0.000 146.352 0.024 146.376 ;
    END
  END wd_in_A[25]
  PIN wd_in_B[25]
    DIRECTION INPUT ;
    USE SIGNAL ;
    SHAPE ABUTMENT ;
    PORT
      LAYER M4 ;
      RECT 51.656 146.352 51.680 146.376 ;
    END
  END wd_in_B[25]
  PIN wd_in_A[26]
    DIRECTION INPUT ;
    USE SIGNAL ;
    SHAPE ABUTMENT ;
    PORT
      LAYER M4 ;
      RECT 0.000 147.984 0.024 148.008 ;
    END
  END wd_in_A[26]
  PIN wd_in_B[26]
    DIRECTION INPUT ;
    USE SIGNAL ;
    SHAPE ABUTMENT ;
    PORT
      LAYER M4 ;
      RECT 51.656 147.984 51.680 148.008 ;
    END
  END wd_in_B[26]
  PIN wd_in_A[27]
    DIRECTION INPUT ;
    USE SIGNAL ;
    SHAPE ABUTMENT ;
    PORT
      LAYER M4 ;
      RECT 0.000 149.616 0.024 149.640 ;
    END
  END wd_in_A[27]
  PIN wd_in_B[27]
    DIRECTION INPUT ;
    USE SIGNAL ;
    SHAPE ABUTMENT ;
    PORT
      LAYER M4 ;
      RECT 51.656 149.616 51.680 149.640 ;
    END
  END wd_in_B[27]
  PIN wd_in_A[28]
    DIRECTION INPUT ;
    USE SIGNAL ;
    SHAPE ABUTMENT ;
    PORT
      LAYER M4 ;
      RECT 0.000 151.248 0.024 151.272 ;
    END
  END wd_in_A[28]
  PIN wd_in_B[28]
    DIRECTION INPUT ;
    USE SIGNAL ;
    SHAPE ABUTMENT ;
    PORT
      LAYER M4 ;
      RECT 51.656 151.248 51.680 151.272 ;
    END
  END wd_in_B[28]
  PIN wd_in_A[29]
    DIRECTION INPUT ;
    USE SIGNAL ;
    SHAPE ABUTMENT ;
    PORT
      LAYER M4 ;
      RECT 0.000 152.880 0.024 152.904 ;
    END
  END wd_in_A[29]
  PIN wd_in_B[29]
    DIRECTION INPUT ;
    USE SIGNAL ;
    SHAPE ABUTMENT ;
    PORT
      LAYER M4 ;
      RECT 51.656 152.880 51.680 152.904 ;
    END
  END wd_in_B[29]
  PIN wd_in_A[30]
    DIRECTION INPUT ;
    USE SIGNAL ;
    SHAPE ABUTMENT ;
    PORT
      LAYER M4 ;
      RECT 0.000 154.512 0.024 154.536 ;
    END
  END wd_in_A[30]
  PIN wd_in_B[30]
    DIRECTION INPUT ;
    USE SIGNAL ;
    SHAPE ABUTMENT ;
    PORT
      LAYER M4 ;
      RECT 51.656 154.512 51.680 154.536 ;
    END
  END wd_in_B[30]
  PIN wd_in_A[31]
    DIRECTION INPUT ;
    USE SIGNAL ;
    SHAPE ABUTMENT ;
    PORT
      LAYER M4 ;
      RECT 0.000 156.144 0.024 156.168 ;
    END
  END wd_in_A[31]
  PIN wd_in_B[31]
    DIRECTION INPUT ;
    USE SIGNAL ;
    SHAPE ABUTMENT ;
    PORT
      LAYER M4 ;
      RECT 51.656 156.144 51.680 156.168 ;
    END
  END wd_in_B[31]
  PIN addr_in_A[0]
    DIRECTION INPUT ;
    USE SIGNAL ;
    SHAPE ABUTMENT ;
    PORT
      LAYER M4 ;
      RECT 0.000 158.304 0.024 158.328 ;
    END
  END addr_in_A[0]
  PIN addr_in_B[0]
    DIRECTION INPUT ;
    USE SIGNAL ;
    SHAPE ABUTMENT ;
    PORT
      LAYER M4 ;
      RECT 51.656 158.304 51.680 158.328 ;
    END
  END addr_in_B[0]
  PIN addr_in_A[1]
    DIRECTION INPUT ;
    USE SIGNAL ;
    SHAPE ABUTMENT ;
    PORT
      LAYER M4 ;
      RECT 0.000 159.936 0.024 159.960 ;
    END
  END addr_in_A[1]
  PIN addr_in_B[1]
    DIRECTION INPUT ;
    USE SIGNAL ;
    SHAPE ABUTMENT ;
    PORT
      LAYER M4 ;
      RECT 51.656 159.936 51.680 159.960 ;
    END
  END addr_in_B[1]
  PIN addr_in_A[2]
    DIRECTION INPUT ;
    USE SIGNAL ;
    SHAPE ABUTMENT ;
    PORT
      LAYER M4 ;
      RECT 0.000 161.568 0.024 161.592 ;
    END
  END addr_in_A[2]
  PIN addr_in_B[2]
    DIRECTION INPUT ;
    USE SIGNAL ;
    SHAPE ABUTMENT ;
    PORT
      LAYER M4 ;
      RECT 51.656 161.568 51.680 161.592 ;
    END
  END addr_in_B[2]
  PIN addr_in_A[3]
    DIRECTION INPUT ;
    USE SIGNAL ;
    SHAPE ABUTMENT ;
    PORT
      LAYER M4 ;
      RECT 0.000 163.200 0.024 163.224 ;
    END
  END addr_in_A[3]
  PIN addr_in_B[3]
    DIRECTION INPUT ;
    USE SIGNAL ;
    SHAPE ABUTMENT ;
    PORT
      LAYER M4 ;
      RECT 51.656 163.200 51.680 163.224 ;
    END
  END addr_in_B[3]
  PIN addr_in_A[4]
    DIRECTION INPUT ;
    USE SIGNAL ;
    SHAPE ABUTMENT ;
    PORT
      LAYER M4 ;
      RECT 0.000 164.832 0.024 164.856 ;
    END
  END addr_in_A[4]
  PIN addr_in_B[4]
    DIRECTION INPUT ;
    USE SIGNAL ;
    SHAPE ABUTMENT ;
    PORT
      LAYER M4 ;
      RECT 51.656 164.832 51.680 164.856 ;
    END
  END addr_in_B[4]
  PIN addr_in_A[5]
    DIRECTION INPUT ;
    USE SIGNAL ;
    SHAPE ABUTMENT ;
    PORT
      LAYER M4 ;
      RECT 0.000 166.464 0.024 166.488 ;
    END
  END addr_in_A[5]
  PIN addr_in_B[5]
    DIRECTION INPUT ;
    USE SIGNAL ;
    SHAPE ABUTMENT ;
    PORT
      LAYER M4 ;
      RECT 51.656 166.464 51.680 166.488 ;
    END
  END addr_in_B[5]
  PIN addr_in_A[6]
    DIRECTION INPUT ;
    USE SIGNAL ;
    SHAPE ABUTMENT ;
    PORT
      LAYER M4 ;
      RECT 0.000 168.096 0.024 168.120 ;
    END
  END addr_in_A[6]
  PIN addr_in_B[6]
    DIRECTION INPUT ;
    USE SIGNAL ;
    SHAPE ABUTMENT ;
    PORT
      LAYER M4 ;
      RECT 51.656 168.096 51.680 168.120 ;
    END
  END addr_in_B[6]
  PIN addr_in_A[7]
    DIRECTION INPUT ;
    USE SIGNAL ;
    SHAPE ABUTMENT ;
    PORT
      LAYER M4 ;
      RECT 0.000 169.728 0.024 169.752 ;
    END
  END addr_in_A[7]
  PIN addr_in_B[7]
    DIRECTION INPUT ;
    USE SIGNAL ;
    SHAPE ABUTMENT ;
    PORT
      LAYER M4 ;
      RECT 51.656 169.728 51.680 169.752 ;
    END
  END addr_in_B[7]
  PIN addr_in_A[8]
    DIRECTION INPUT ;
    USE SIGNAL ;
    SHAPE ABUTMENT ;
    PORT
      LAYER M4 ;
      RECT 0.000 171.360 0.024 171.384 ;
    END
  END addr_in_A[8]
  PIN addr_in_B[8]
    DIRECTION INPUT ;
    USE SIGNAL ;
    SHAPE ABUTMENT ;
    PORT
      LAYER M4 ;
      RECT 51.656 171.360 51.680 171.384 ;
    END
  END addr_in_B[8]
  PIN addr_in_A[9]
    DIRECTION INPUT ;
    USE SIGNAL ;
    SHAPE ABUTMENT ;
    PORT
      LAYER M4 ;
      RECT 0.000 172.992 0.024 173.016 ;
    END
  END addr_in_A[9]
  PIN addr_in_B[9]
    DIRECTION INPUT ;
    USE SIGNAL ;
    SHAPE ABUTMENT ;
    PORT
      LAYER M4 ;
      RECT 51.656 172.992 51.680 173.016 ;
    END
  END addr_in_B[9]
  PIN addr_in_A[10]
    DIRECTION INPUT ;
    USE SIGNAL ;
    SHAPE ABUTMENT ;
    PORT
      LAYER M4 ;
      RECT 0.000 174.624 0.024 174.648 ;
    END
  END addr_in_A[10]
  PIN addr_in_B[10]
    DIRECTION INPUT ;
    USE SIGNAL ;
    SHAPE ABUTMENT ;
    PORT
      LAYER M4 ;
      RECT 51.656 174.624 51.680 174.648 ;
    END
  END addr_in_B[10]
  PIN addr_in_A[11]
    DIRECTION INPUT ;
    USE SIGNAL ;
    SHAPE ABUTMENT ;
    PORT
      LAYER M4 ;
      RECT 0.000 176.256 0.024 176.280 ;
    END
  END addr_in_A[11]
  PIN addr_in_B[11]
    DIRECTION INPUT ;
    USE SIGNAL ;
    SHAPE ABUTMENT ;
    PORT
      LAYER M4 ;
      RECT 51.656 176.256 51.680 176.280 ;
    END
  END addr_in_B[11]
  PIN we_in_A
    DIRECTION INPUT ;
    USE SIGNAL ;
    SHAPE ABUTMENT ;
    PORT
      LAYER M4 ;
      RECT 0.000 178.416 0.024 178.440 ;
    END
  END we_in_A
  PIN we_in_B
    DIRECTION INPUT ;
    USE SIGNAL ;
    SHAPE ABUTMENT ;
    PORT
      LAYER M4 ;
      RECT 51.656 178.416 51.680 178.440 ;
    END
  END we_in_B
  PIN ce_in_A
    DIRECTION INPUT ;
    USE SIGNAL ;
    SHAPE ABUTMENT ;
    PORT
      LAYER M4 ;
      RECT 0.000 180.048 0.024 180.072 ;
    END
  END ce_in_A
  PIN clk_A
    DIRECTION INPUT ;
    USE SIGNAL ;
    SHAPE ABUTMENT ;
    PORT
      LAYER M4 ;
      RECT 0.000 181.680 0.024 181.704 ;
    END
  END clk_A
  PIN ce_in_B
    DIRECTION INPUT ;
    USE SIGNAL ;
    SHAPE ABUTMENT ;
    PORT
      LAYER M4 ;
      RECT 0.000 183.312 0.024 183.336 ;
    END
  END ce_in_B
  PIN clk_B
    DIRECTION INPUT ;
    USE SIGNAL ;
    SHAPE ABUTMENT ;
    PORT
      LAYER M4 ;
      RECT 0.000 184.944 0.024 184.968 ;
    END
  END clk_B
  PIN VSS
    DIRECTION INOUT ;
    USE GROUND ;
    PORT
      LAYER M4 ;
      RECT 0.048 0.000 51.632 0.096 ;
      RECT 0.048 0.768 51.632 0.864 ;
      RECT 0.048 1.536 51.632 1.632 ;
      RECT 0.048 2.304 51.632 2.400 ;
      RECT 0.048 3.072 51.632 3.168 ;
      RECT 0.048 3.840 51.632 3.936 ;
      RECT 0.048 4.608 51.632 4.704 ;
      RECT 0.048 5.376 51.632 5.472 ;
      RECT 0.048 6.144 51.632 6.240 ;
      RECT 0.048 6.912 51.632 7.008 ;
      RECT 0.048 7.680 51.632 7.776 ;
      RECT 0.048 8.448 51.632 8.544 ;
      RECT 0.048 9.216 51.632 9.312 ;
      RECT 0.048 9.984 51.632 10.080 ;
      RECT 0.048 10.752 51.632 10.848 ;
      RECT 0.048 11.520 51.632 11.616 ;
      RECT 0.048 12.288 51.632 12.384 ;
      RECT 0.048 13.056 51.632 13.152 ;
      RECT 0.048 13.824 51.632 13.920 ;
      RECT 0.048 14.592 51.632 14.688 ;
      RECT 0.048 15.360 51.632 15.456 ;
      RECT 0.048 16.128 51.632 16.224 ;
      RECT 0.048 16.896 51.632 16.992 ;
      RECT 0.048 17.664 51.632 17.760 ;
      RECT 0.048 18.432 51.632 18.528 ;
      RECT 0.048 19.200 51.632 19.296 ;
      RECT 0.048 19.968 51.632 20.064 ;
      RECT 0.048 20.736 51.632 20.832 ;
      RECT 0.048 21.504 51.632 21.600 ;
      RECT 0.048 22.272 51.632 22.368 ;
      RECT 0.048 23.040 51.632 23.136 ;
      RECT 0.048 23.808 51.632 23.904 ;
      RECT 0.048 24.576 51.632 24.672 ;
      RECT 0.048 25.344 51.632 25.440 ;
      RECT 0.048 26.112 51.632 26.208 ;
      RECT 0.048 26.880 51.632 26.976 ;
      RECT 0.048 27.648 51.632 27.744 ;
      RECT 0.048 28.416 51.632 28.512 ;
      RECT 0.048 29.184 51.632 29.280 ;
      RECT 0.048 29.952 51.632 30.048 ;
      RECT 0.048 30.720 51.632 30.816 ;
      RECT 0.048 31.488 51.632 31.584 ;
      RECT 0.048 32.256 51.632 32.352 ;
      RECT 0.048 33.024 51.632 33.120 ;
      RECT 0.048 33.792 51.632 33.888 ;
      RECT 0.048 34.560 51.632 34.656 ;
      RECT 0.048 35.328 51.632 35.424 ;
      RECT 0.048 36.096 51.632 36.192 ;
      RECT 0.048 36.864 51.632 36.960 ;
      RECT 0.048 37.632 51.632 37.728 ;
      RECT 0.048 38.400 51.632 38.496 ;
      RECT 0.048 39.168 51.632 39.264 ;
      RECT 0.048 39.936 51.632 40.032 ;
      RECT 0.048 40.704 51.632 40.800 ;
      RECT 0.048 41.472 51.632 41.568 ;
      RECT 0.048 42.240 51.632 42.336 ;
      RECT 0.048 43.008 51.632 43.104 ;
      RECT 0.048 43.776 51.632 43.872 ;
      RECT 0.048 44.544 51.632 44.640 ;
      RECT 0.048 45.312 51.632 45.408 ;
      RECT 0.048 46.080 51.632 46.176 ;
      RECT 0.048 46.848 51.632 46.944 ;
      RECT 0.048 47.616 51.632 47.712 ;
      RECT 0.048 48.384 51.632 48.480 ;
      RECT 0.048 49.152 51.632 49.248 ;
      RECT 0.048 49.920 51.632 50.016 ;
      RECT 0.048 50.688 51.632 50.784 ;
      RECT 0.048 51.456 51.632 51.552 ;
      RECT 0.048 52.224 51.632 52.320 ;
      RECT 0.048 52.992 51.632 53.088 ;
      RECT 0.048 53.760 51.632 53.856 ;
      RECT 0.048 54.528 51.632 54.624 ;
      RECT 0.048 55.296 51.632 55.392 ;
      RECT 0.048 56.064 51.632 56.160 ;
      RECT 0.048 56.832 51.632 56.928 ;
      RECT 0.048 57.600 51.632 57.696 ;
      RECT 0.048 58.368 51.632 58.464 ;
      RECT 0.048 59.136 51.632 59.232 ;
      RECT 0.048 59.904 51.632 60.000 ;
      RECT 0.048 60.672 51.632 60.768 ;
      RECT 0.048 61.440 51.632 61.536 ;
      RECT 0.048 62.208 51.632 62.304 ;
      RECT 0.048 62.976 51.632 63.072 ;
      RECT 0.048 63.744 51.632 63.840 ;
      RECT 0.048 64.512 51.632 64.608 ;
      RECT 0.048 65.280 51.632 65.376 ;
      RECT 0.048 66.048 51.632 66.144 ;
      RECT 0.048 66.816 51.632 66.912 ;
      RECT 0.048 67.584 51.632 67.680 ;
      RECT 0.048 68.352 51.632 68.448 ;
      RECT 0.048 69.120 51.632 69.216 ;
      RECT 0.048 69.888 51.632 69.984 ;
      RECT 0.048 70.656 51.632 70.752 ;
      RECT 0.048 71.424 51.632 71.520 ;
      RECT 0.048 72.192 51.632 72.288 ;
      RECT 0.048 72.960 51.632 73.056 ;
      RECT 0.048 73.728 51.632 73.824 ;
      RECT 0.048 74.496 51.632 74.592 ;
      RECT 0.048 75.264 51.632 75.360 ;
      RECT 0.048 76.032 51.632 76.128 ;
      RECT 0.048 76.800 51.632 76.896 ;
      RECT 0.048 77.568 51.632 77.664 ;
      RECT 0.048 78.336 51.632 78.432 ;
      RECT 0.048 79.104 51.632 79.200 ;
      RECT 0.048 79.872 51.632 79.968 ;
      RECT 0.048 80.640 51.632 80.736 ;
      RECT 0.048 81.408 51.632 81.504 ;
      RECT 0.048 82.176 51.632 82.272 ;
      RECT 0.048 82.944 51.632 83.040 ;
      RECT 0.048 83.712 51.632 83.808 ;
      RECT 0.048 84.480 51.632 84.576 ;
      RECT 0.048 85.248 51.632 85.344 ;
      RECT 0.048 86.016 51.632 86.112 ;
      RECT 0.048 86.784 51.632 86.880 ;
      RECT 0.048 87.552 51.632 87.648 ;
      RECT 0.048 88.320 51.632 88.416 ;
      RECT 0.048 89.088 51.632 89.184 ;
      RECT 0.048 89.856 51.632 89.952 ;
      RECT 0.048 90.624 51.632 90.720 ;
      RECT 0.048 91.392 51.632 91.488 ;
      RECT 0.048 92.160 51.632 92.256 ;
      RECT 0.048 92.928 51.632 93.024 ;
      RECT 0.048 93.696 51.632 93.792 ;
      RECT 0.048 94.464 51.632 94.560 ;
      RECT 0.048 95.232 51.632 95.328 ;
      RECT 0.048 96.000 51.632 96.096 ;
      RECT 0.048 96.768 51.632 96.864 ;
      RECT 0.048 97.536 51.632 97.632 ;
      RECT 0.048 98.304 51.632 98.400 ;
      RECT 0.048 99.072 51.632 99.168 ;
      RECT 0.048 99.840 51.632 99.936 ;
      RECT 0.048 100.608 51.632 100.704 ;
      RECT 0.048 101.376 51.632 101.472 ;
      RECT 0.048 102.144 51.632 102.240 ;
      RECT 0.048 102.912 51.632 103.008 ;
      RECT 0.048 103.680 51.632 103.776 ;
      RECT 0.048 104.448 51.632 104.544 ;
      RECT 0.048 105.216 51.632 105.312 ;
      RECT 0.048 105.984 51.632 106.080 ;
      RECT 0.048 106.752 51.632 106.848 ;
      RECT 0.048 107.520 51.632 107.616 ;
      RECT 0.048 108.288 51.632 108.384 ;
      RECT 0.048 109.056 51.632 109.152 ;
      RECT 0.048 109.824 51.632 109.920 ;
      RECT 0.048 110.592 51.632 110.688 ;
      RECT 0.048 111.360 51.632 111.456 ;
      RECT 0.048 112.128 51.632 112.224 ;
      RECT 0.048 112.896 51.632 112.992 ;
      RECT 0.048 113.664 51.632 113.760 ;
      RECT 0.048 114.432 51.632 114.528 ;
      RECT 0.048 115.200 51.632 115.296 ;
      RECT 0.048 115.968 51.632 116.064 ;
      RECT 0.048 116.736 51.632 116.832 ;
      RECT 0.048 117.504 51.632 117.600 ;
      RECT 0.048 118.272 51.632 118.368 ;
      RECT 0.048 119.040 51.632 119.136 ;
      RECT 0.048 119.808 51.632 119.904 ;
      RECT 0.048 120.576 51.632 120.672 ;
      RECT 0.048 121.344 51.632 121.440 ;
      RECT 0.048 122.112 51.632 122.208 ;
      RECT 0.048 122.880 51.632 122.976 ;
      RECT 0.048 123.648 51.632 123.744 ;
      RECT 0.048 124.416 51.632 124.512 ;
      RECT 0.048 125.184 51.632 125.280 ;
      RECT 0.048 125.952 51.632 126.048 ;
      RECT 0.048 126.720 51.632 126.816 ;
      RECT 0.048 127.488 51.632 127.584 ;
      RECT 0.048 128.256 51.632 128.352 ;
      RECT 0.048 129.024 51.632 129.120 ;
      RECT 0.048 129.792 51.632 129.888 ;
      RECT 0.048 130.560 51.632 130.656 ;
      RECT 0.048 131.328 51.632 131.424 ;
      RECT 0.048 132.096 51.632 132.192 ;
      RECT 0.048 132.864 51.632 132.960 ;
      RECT 0.048 133.632 51.632 133.728 ;
      RECT 0.048 134.400 51.632 134.496 ;
      RECT 0.048 135.168 51.632 135.264 ;
      RECT 0.048 135.936 51.632 136.032 ;
      RECT 0.048 136.704 51.632 136.800 ;
      RECT 0.048 137.472 51.632 137.568 ;
      RECT 0.048 138.240 51.632 138.336 ;
      RECT 0.048 139.008 51.632 139.104 ;
      RECT 0.048 139.776 51.632 139.872 ;
      RECT 0.048 140.544 51.632 140.640 ;
      RECT 0.048 141.312 51.632 141.408 ;
      RECT 0.048 142.080 51.632 142.176 ;
      RECT 0.048 142.848 51.632 142.944 ;
      RECT 0.048 143.616 51.632 143.712 ;
      RECT 0.048 144.384 51.632 144.480 ;
      RECT 0.048 145.152 51.632 145.248 ;
      RECT 0.048 145.920 51.632 146.016 ;
      RECT 0.048 146.688 51.632 146.784 ;
      RECT 0.048 147.456 51.632 147.552 ;
      RECT 0.048 148.224 51.632 148.320 ;
      RECT 0.048 148.992 51.632 149.088 ;
      RECT 0.048 149.760 51.632 149.856 ;
      RECT 0.048 150.528 51.632 150.624 ;
      RECT 0.048 151.296 51.632 151.392 ;
      RECT 0.048 152.064 51.632 152.160 ;
      RECT 0.048 152.832 51.632 152.928 ;
      RECT 0.048 153.600 51.632 153.696 ;
      RECT 0.048 154.368 51.632 154.464 ;
      RECT 0.048 155.136 51.632 155.232 ;
      RECT 0.048 155.904 51.632 156.000 ;
      RECT 0.048 156.672 51.632 156.768 ;
      RECT 0.048 157.440 51.632 157.536 ;
      RECT 0.048 158.208 51.632 158.304 ;
      RECT 0.048 158.976 51.632 159.072 ;
      RECT 0.048 159.744 51.632 159.840 ;
      RECT 0.048 160.512 51.632 160.608 ;
      RECT 0.048 161.280 51.632 161.376 ;
      RECT 0.048 162.048 51.632 162.144 ;
      RECT 0.048 162.816 51.632 162.912 ;
      RECT 0.048 163.584 51.632 163.680 ;
      RECT 0.048 164.352 51.632 164.448 ;
      RECT 0.048 165.120 51.632 165.216 ;
      RECT 0.048 165.888 51.632 165.984 ;
      RECT 0.048 166.656 51.632 166.752 ;
      RECT 0.048 167.424 51.632 167.520 ;
      RECT 0.048 168.192 51.632 168.288 ;
      RECT 0.048 168.960 51.632 169.056 ;
      RECT 0.048 169.728 51.632 169.824 ;
      RECT 0.048 170.496 51.632 170.592 ;
      RECT 0.048 171.264 51.632 171.360 ;
      RECT 0.048 172.032 51.632 172.128 ;
      RECT 0.048 172.800 51.632 172.896 ;
      RECT 0.048 173.568 51.632 173.664 ;
      RECT 0.048 174.336 51.632 174.432 ;
      RECT 0.048 175.104 51.632 175.200 ;
      RECT 0.048 175.872 51.632 175.968 ;
      RECT 0.048 176.640 51.632 176.736 ;
      RECT 0.048 177.408 51.632 177.504 ;
      RECT 0.048 178.176 51.632 178.272 ;
      RECT 0.048 178.944 51.632 179.040 ;
      RECT 0.048 179.712 51.632 179.808 ;
      RECT 0.048 180.480 51.632 180.576 ;
      RECT 0.048 181.248 51.632 181.344 ;
      RECT 0.048 182.016 51.632 182.112 ;
      RECT 0.048 182.784 51.632 182.880 ;
    END
  END VSS
  PIN VDD
    DIRECTION INOUT ;
    USE POWER ;
    PORT
      LAYER M4 ;
      RECT 0.048 0.384 51.632 0.480 ;
      RECT 0.048 1.152 51.632 1.248 ;
      RECT 0.048 1.920 51.632 2.016 ;
      RECT 0.048 2.688 51.632 2.784 ;
      RECT 0.048 3.456 51.632 3.552 ;
      RECT 0.048 4.224 51.632 4.320 ;
      RECT 0.048 4.992 51.632 5.088 ;
      RECT 0.048 5.760 51.632 5.856 ;
      RECT 0.048 6.528 51.632 6.624 ;
      RECT 0.048 7.296 51.632 7.392 ;
      RECT 0.048 8.064 51.632 8.160 ;
      RECT 0.048 8.832 51.632 8.928 ;
      RECT 0.048 9.600 51.632 9.696 ;
      RECT 0.048 10.368 51.632 10.464 ;
      RECT 0.048 11.136 51.632 11.232 ;
      RECT 0.048 11.904 51.632 12.000 ;
      RECT 0.048 12.672 51.632 12.768 ;
      RECT 0.048 13.440 51.632 13.536 ;
      RECT 0.048 14.208 51.632 14.304 ;
      RECT 0.048 14.976 51.632 15.072 ;
      RECT 0.048 15.744 51.632 15.840 ;
      RECT 0.048 16.512 51.632 16.608 ;
      RECT 0.048 17.280 51.632 17.376 ;
      RECT 0.048 18.048 51.632 18.144 ;
      RECT 0.048 18.816 51.632 18.912 ;
      RECT 0.048 19.584 51.632 19.680 ;
      RECT 0.048 20.352 51.632 20.448 ;
      RECT 0.048 21.120 51.632 21.216 ;
      RECT 0.048 21.888 51.632 21.984 ;
      RECT 0.048 22.656 51.632 22.752 ;
      RECT 0.048 23.424 51.632 23.520 ;
      RECT 0.048 24.192 51.632 24.288 ;
      RECT 0.048 24.960 51.632 25.056 ;
      RECT 0.048 25.728 51.632 25.824 ;
      RECT 0.048 26.496 51.632 26.592 ;
      RECT 0.048 27.264 51.632 27.360 ;
      RECT 0.048 28.032 51.632 28.128 ;
      RECT 0.048 28.800 51.632 28.896 ;
      RECT 0.048 29.568 51.632 29.664 ;
      RECT 0.048 30.336 51.632 30.432 ;
      RECT 0.048 31.104 51.632 31.200 ;
      RECT 0.048 31.872 51.632 31.968 ;
      RECT 0.048 32.640 51.632 32.736 ;
      RECT 0.048 33.408 51.632 33.504 ;
      RECT 0.048 34.176 51.632 34.272 ;
      RECT 0.048 34.944 51.632 35.040 ;
      RECT 0.048 35.712 51.632 35.808 ;
      RECT 0.048 36.480 51.632 36.576 ;
      RECT 0.048 37.248 51.632 37.344 ;
      RECT 0.048 38.016 51.632 38.112 ;
      RECT 0.048 38.784 51.632 38.880 ;
      RECT 0.048 39.552 51.632 39.648 ;
      RECT 0.048 40.320 51.632 40.416 ;
      RECT 0.048 41.088 51.632 41.184 ;
      RECT 0.048 41.856 51.632 41.952 ;
      RECT 0.048 42.624 51.632 42.720 ;
      RECT 0.048 43.392 51.632 43.488 ;
      RECT 0.048 44.160 51.632 44.256 ;
      RECT 0.048 44.928 51.632 45.024 ;
      RECT 0.048 45.696 51.632 45.792 ;
      RECT 0.048 46.464 51.632 46.560 ;
      RECT 0.048 47.232 51.632 47.328 ;
      RECT 0.048 48.000 51.632 48.096 ;
      RECT 0.048 48.768 51.632 48.864 ;
      RECT 0.048 49.536 51.632 49.632 ;
      RECT 0.048 50.304 51.632 50.400 ;
      RECT 0.048 51.072 51.632 51.168 ;
      RECT 0.048 51.840 51.632 51.936 ;
      RECT 0.048 52.608 51.632 52.704 ;
      RECT 0.048 53.376 51.632 53.472 ;
      RECT 0.048 54.144 51.632 54.240 ;
      RECT 0.048 54.912 51.632 55.008 ;
      RECT 0.048 55.680 51.632 55.776 ;
      RECT 0.048 56.448 51.632 56.544 ;
      RECT 0.048 57.216 51.632 57.312 ;
      RECT 0.048 57.984 51.632 58.080 ;
      RECT 0.048 58.752 51.632 58.848 ;
      RECT 0.048 59.520 51.632 59.616 ;
      RECT 0.048 60.288 51.632 60.384 ;
      RECT 0.048 61.056 51.632 61.152 ;
      RECT 0.048 61.824 51.632 61.920 ;
      RECT 0.048 62.592 51.632 62.688 ;
      RECT 0.048 63.360 51.632 63.456 ;
      RECT 0.048 64.128 51.632 64.224 ;
      RECT 0.048 64.896 51.632 64.992 ;
      RECT 0.048 65.664 51.632 65.760 ;
      RECT 0.048 66.432 51.632 66.528 ;
      RECT 0.048 67.200 51.632 67.296 ;
      RECT 0.048 67.968 51.632 68.064 ;
      RECT 0.048 68.736 51.632 68.832 ;
      RECT 0.048 69.504 51.632 69.600 ;
      RECT 0.048 70.272 51.632 70.368 ;
      RECT 0.048 71.040 51.632 71.136 ;
      RECT 0.048 71.808 51.632 71.904 ;
      RECT 0.048 72.576 51.632 72.672 ;
      RECT 0.048 73.344 51.632 73.440 ;
      RECT 0.048 74.112 51.632 74.208 ;
      RECT 0.048 74.880 51.632 74.976 ;
      RECT 0.048 75.648 51.632 75.744 ;
      RECT 0.048 76.416 51.632 76.512 ;
      RECT 0.048 77.184 51.632 77.280 ;
      RECT 0.048 77.952 51.632 78.048 ;
      RECT 0.048 78.720 51.632 78.816 ;
      RECT 0.048 79.488 51.632 79.584 ;
      RECT 0.048 80.256 51.632 80.352 ;
      RECT 0.048 81.024 51.632 81.120 ;
      RECT 0.048 81.792 51.632 81.888 ;
      RECT 0.048 82.560 51.632 82.656 ;
      RECT 0.048 83.328 51.632 83.424 ;
      RECT 0.048 84.096 51.632 84.192 ;
      RECT 0.048 84.864 51.632 84.960 ;
      RECT 0.048 85.632 51.632 85.728 ;
      RECT 0.048 86.400 51.632 86.496 ;
      RECT 0.048 87.168 51.632 87.264 ;
      RECT 0.048 87.936 51.632 88.032 ;
      RECT 0.048 88.704 51.632 88.800 ;
      RECT 0.048 89.472 51.632 89.568 ;
      RECT 0.048 90.240 51.632 90.336 ;
      RECT 0.048 91.008 51.632 91.104 ;
      RECT 0.048 91.776 51.632 91.872 ;
      RECT 0.048 92.544 51.632 92.640 ;
      RECT 0.048 93.312 51.632 93.408 ;
      RECT 0.048 94.080 51.632 94.176 ;
      RECT 0.048 94.848 51.632 94.944 ;
      RECT 0.048 95.616 51.632 95.712 ;
      RECT 0.048 96.384 51.632 96.480 ;
      RECT 0.048 97.152 51.632 97.248 ;
      RECT 0.048 97.920 51.632 98.016 ;
      RECT 0.048 98.688 51.632 98.784 ;
      RECT 0.048 99.456 51.632 99.552 ;
      RECT 0.048 100.224 51.632 100.320 ;
      RECT 0.048 100.992 51.632 101.088 ;
      RECT 0.048 101.760 51.632 101.856 ;
      RECT 0.048 102.528 51.632 102.624 ;
      RECT 0.048 103.296 51.632 103.392 ;
      RECT 0.048 104.064 51.632 104.160 ;
      RECT 0.048 104.832 51.632 104.928 ;
      RECT 0.048 105.600 51.632 105.696 ;
      RECT 0.048 106.368 51.632 106.464 ;
      RECT 0.048 107.136 51.632 107.232 ;
      RECT 0.048 107.904 51.632 108.000 ;
      RECT 0.048 108.672 51.632 108.768 ;
      RECT 0.048 109.440 51.632 109.536 ;
      RECT 0.048 110.208 51.632 110.304 ;
      RECT 0.048 110.976 51.632 111.072 ;
      RECT 0.048 111.744 51.632 111.840 ;
      RECT 0.048 112.512 51.632 112.608 ;
      RECT 0.048 113.280 51.632 113.376 ;
      RECT 0.048 114.048 51.632 114.144 ;
      RECT 0.048 114.816 51.632 114.912 ;
      RECT 0.048 115.584 51.632 115.680 ;
      RECT 0.048 116.352 51.632 116.448 ;
      RECT 0.048 117.120 51.632 117.216 ;
      RECT 0.048 117.888 51.632 117.984 ;
      RECT 0.048 118.656 51.632 118.752 ;
      RECT 0.048 119.424 51.632 119.520 ;
      RECT 0.048 120.192 51.632 120.288 ;
      RECT 0.048 120.960 51.632 121.056 ;
      RECT 0.048 121.728 51.632 121.824 ;
      RECT 0.048 122.496 51.632 122.592 ;
      RECT 0.048 123.264 51.632 123.360 ;
      RECT 0.048 124.032 51.632 124.128 ;
      RECT 0.048 124.800 51.632 124.896 ;
      RECT 0.048 125.568 51.632 125.664 ;
      RECT 0.048 126.336 51.632 126.432 ;
      RECT 0.048 127.104 51.632 127.200 ;
      RECT 0.048 127.872 51.632 127.968 ;
      RECT 0.048 128.640 51.632 128.736 ;
      RECT 0.048 129.408 51.632 129.504 ;
      RECT 0.048 130.176 51.632 130.272 ;
      RECT 0.048 130.944 51.632 131.040 ;
      RECT 0.048 131.712 51.632 131.808 ;
      RECT 0.048 132.480 51.632 132.576 ;
      RECT 0.048 133.248 51.632 133.344 ;
      RECT 0.048 134.016 51.632 134.112 ;
      RECT 0.048 134.784 51.632 134.880 ;
      RECT 0.048 135.552 51.632 135.648 ;
      RECT 0.048 136.320 51.632 136.416 ;
      RECT 0.048 137.088 51.632 137.184 ;
      RECT 0.048 137.856 51.632 137.952 ;
      RECT 0.048 138.624 51.632 138.720 ;
      RECT 0.048 139.392 51.632 139.488 ;
      RECT 0.048 140.160 51.632 140.256 ;
      RECT 0.048 140.928 51.632 141.024 ;
      RECT 0.048 141.696 51.632 141.792 ;
      RECT 0.048 142.464 51.632 142.560 ;
      RECT 0.048 143.232 51.632 143.328 ;
      RECT 0.048 144.000 51.632 144.096 ;
      RECT 0.048 144.768 51.632 144.864 ;
      RECT 0.048 145.536 51.632 145.632 ;
      RECT 0.048 146.304 51.632 146.400 ;
      RECT 0.048 147.072 51.632 147.168 ;
      RECT 0.048 147.840 51.632 147.936 ;
      RECT 0.048 148.608 51.632 148.704 ;
      RECT 0.048 149.376 51.632 149.472 ;
      RECT 0.048 150.144 51.632 150.240 ;
      RECT 0.048 150.912 51.632 151.008 ;
      RECT 0.048 151.680 51.632 151.776 ;
      RECT 0.048 152.448 51.632 152.544 ;
      RECT 0.048 153.216 51.632 153.312 ;
      RECT 0.048 153.984 51.632 154.080 ;
      RECT 0.048 154.752 51.632 154.848 ;
      RECT 0.048 155.520 51.632 155.616 ;
      RECT 0.048 156.288 51.632 156.384 ;
      RECT 0.048 157.056 51.632 157.152 ;
      RECT 0.048 157.824 51.632 157.920 ;
      RECT 0.048 158.592 51.632 158.688 ;
      RECT 0.048 159.360 51.632 159.456 ;
      RECT 0.048 160.128 51.632 160.224 ;
      RECT 0.048 160.896 51.632 160.992 ;
      RECT 0.048 161.664 51.632 161.760 ;
      RECT 0.048 162.432 51.632 162.528 ;
      RECT 0.048 163.200 51.632 163.296 ;
      RECT 0.048 163.968 51.632 164.064 ;
      RECT 0.048 164.736 51.632 164.832 ;
      RECT 0.048 165.504 51.632 165.600 ;
      RECT 0.048 166.272 51.632 166.368 ;
      RECT 0.048 167.040 51.632 167.136 ;
      RECT 0.048 167.808 51.632 167.904 ;
      RECT 0.048 168.576 51.632 168.672 ;
      RECT 0.048 169.344 51.632 169.440 ;
      RECT 0.048 170.112 51.632 170.208 ;
      RECT 0.048 170.880 51.632 170.976 ;
      RECT 0.048 171.648 51.632 171.744 ;
      RECT 0.048 172.416 51.632 172.512 ;
      RECT 0.048 173.184 51.632 173.280 ;
      RECT 0.048 173.952 51.632 174.048 ;
      RECT 0.048 174.720 51.632 174.816 ;
      RECT 0.048 175.488 51.632 175.584 ;
      RECT 0.048 176.256 51.632 176.352 ;
      RECT 0.048 177.024 51.632 177.120 ;
      RECT 0.048 177.792 51.632 177.888 ;
      RECT 0.048 178.560 51.632 178.656 ;
      RECT 0.048 179.328 51.632 179.424 ;
      RECT 0.048 180.096 51.632 180.192 ;
      RECT 0.048 180.864 51.632 180.960 ;
      RECT 0.048 181.632 51.632 181.728 ;
      RECT 0.048 182.400 51.632 182.496 ;
      RECT 0.048 183.168 51.632 183.264 ;
    END
  END VDD
  OBS
    LAYER M1 ;
    RECT 0 0 51.680 183.400 ;
    LAYER M2 ;
    RECT 0 0 51.680 183.400 ;
    LAYER M3 ;
    RECT 0 0 51.680 183.400 ;
    LAYER M4 ;
    RECT 0 0 51.680 183.400 ;
  END
END fakeram7_tdp_4096x32

END LIBRARY
